###############################################################
#  Generated by:      Cadence Innovus 20.13-s083_1
#  OS:                Linux x86_64(Host ID rice-503-20-north)
#  Generated on:      Sat May 28 16:40:42 2022
#  Design:            bgr_top
#  Command:           write_lef_abstract -specifyTopLayer 6 -PGPinLayers {5 6} -noCutObs -stripePin results/bgr_top.lef
###############################################################

VERSION 5.8 ;

BUSBITCHARS "[]" ;
DIVIDERCHAR "/" ;

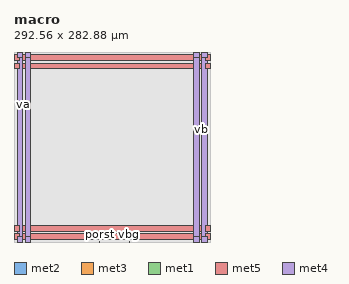
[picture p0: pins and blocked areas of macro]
MACRO macro
  CLASS BLOCK ;
  SIZE 292.560000 BY 282.880000 ;
  FOREIGN macro 0.000000 0.000000 ;
  ORIGIN 0 0 ;
  SYMMETRY X Y R90 ;
  PIN porst
    DIRECTION INOUT ;
    USE SIGNAL ;
    ANTENNAPARTIALMETALAREA 17.5123 LAYER met2  ;
    ANTENNAPARTIALMETALSIDEAREA 87.3355 LAYER met2  ;
    ANTENNAMODEL OXIDE1 ;
    ANTENNAGATEAREA 72 LAYER met2  ;
    ANTENNAMAXAREACAR 0.330333 LAYER met2  ;
    ANTENNAMAXSIDEAREACAR 1.27908 LAYER met2  ;
    ANTENNAMAXCUTCAR 0.000713889 LAYER via2  ;
    PORT
      LAYER met2 ;
        RECT 127.580000 0.000000 127.720000 0.485000 ;
    END
  END porst
  PIN va
    DIRECTION INOUT ;
    USE SIGNAL ;
    ANTENNAPARTIALMETALAREA 10.7926 LAYER met3  ;
    ANTENNAPARTIALMETALSIDEAREA 57.552 LAYER met3  ;
    ANTENNAPARTIALCUTAREA 0.04 LAYER via3  ;
    ANTENNADIFFAREA 82.639 LAYER met4  ;
    ANTENNAPARTIALMETALAREA 158.729 LAYER met4  ;
    ANTENNAPARTIALMETALSIDEAREA 645.352 LAYER met4  ;
    ANTENNAMODEL OXIDE1 ;
    ANTENNAGATEAREA 72 LAYER met4  ;
    ANTENNAMAXAREACAR 2.50947 LAYER met4  ;
    ANTENNAMAXSIDEAREACAR 10.1344 LAYER met4  ;
    ANTENNAMAXCUTCAR 0.00293611 LAYER via4  ;
    PORT
      LAYER met3 ;
        RECT 0.000000 204.870000 0.800000 205.170000 ;
    END
  END va
  PIN vb
    DIRECTION INOUT ;
    USE SIGNAL ;
    ANTENNAPARTIALMETALAREA 7.1098 LAYER met1  ;
    ANTENNAPARTIALMETALSIDEAREA 35.441 LAYER met1  ;
    ANTENNAPARTIALCUTAREA 0.0225 LAYER via  ;
    ANTENNADIFFAREA 57.9855 LAYER met2  ;
    ANTENNAPARTIALMETALAREA 18.9112 LAYER met2  ;
    ANTENNAPARTIALMETALSIDEAREA 93.996 LAYER met2  ;
    ANTENNAMODEL OXIDE1 ;
    ANTENNAGATEAREA 72 LAYER met2  ;
    ANTENNAMAXAREACAR 0.416727 LAYER met2  ;
    ANTENNAMAXSIDEAREACAR 1.70516 LAYER met2  ;
    ANTENNAMAXCUTCAR 0.000713889 LAYER via2  ;
    PORT
      LAYER met1 ;
        RECT 291.965000 167.040000 292.560000 167.180000 ;
    END
  END vb
  PIN vbg
    DIRECTION INOUT ;
    USE SIGNAL ;
    ANTENNADIFFAREA 57.9855 LAYER met2  ;
    ANTENNAPARTIALMETALAREA 16.6079 LAYER met2  ;
    ANTENNAPARTIALMETALSIDEAREA 82.8135 LAYER met2  ;
    PORT
      LAYER met2 ;
        RECT 171.740000 0.000000 171.880000 0.485000 ;
    END
  END vbg
  PIN VDD
    DIRECTION INOUT ;
    USE POWER ;
    PORT
      LAYER met5 ;
        RECT 284.400000 258.240000 292.560000 266.400000 ;
    END
    PORT
      LAYER met5 ;
        RECT 0.000000 258.240000 8.160000 266.400000 ;
    END
    PORT
      LAYER met5 ;
        RECT 284.400000 16.320000 292.560000 24.480000 ;
    END
    PORT
      LAYER met5 ;
        RECT 0.000000 16.320000 8.160000 24.480000 ;
    END
    PORT
      LAYER met4 ;
        RECT 267.280000 274.720000 275.440000 282.880000 ;
    END
    PORT
      LAYER met4 ;
        RECT 267.280000 0.000000 275.440000 8.160000 ;
    END
    PORT
      LAYER met4 ;
        RECT 16.740000 274.720000 24.900000 282.880000 ;
    END
    PORT
      LAYER met4 ;
        RECT 16.740000 0.000000 24.900000 8.160000 ;
    END

# P/G power stripe data as pin
    PORT
      LAYER met4 ;
        RECT 267.280000 0.000000 275.440000 282.880000 ;
        RECT 16.740000 0.000000 24.900000 282.880000 ;
      LAYER met5 ;
        RECT 0.000000 16.320000 292.560000 24.480000 ;
        RECT 0.000000 258.240000 292.560000 266.400000 ;
    END
# end of P/G power stripe data as pin

  END VDD
  PIN VSS
    DIRECTION INOUT ;
    USE GROUND ;
    PORT
      LAYER met5 ;
        RECT 284.400000 270.480000 292.560000 278.640000 ;
    END
    PORT
      LAYER met5 ;
        RECT 0.000000 270.480000 8.160000 278.640000 ;
    END
    PORT
      LAYER met5 ;
        RECT 284.400000 4.080000 292.560000 12.240000 ;
    END
    PORT
      LAYER met5 ;
        RECT 0.000000 4.080000 8.160000 12.240000 ;
    END
    PORT
      LAYER met4 ;
        RECT 279.520000 274.720000 287.680000 282.880000 ;
    END
    PORT
      LAYER met4 ;
        RECT 279.520000 0.000000 287.680000 8.160000 ;
    END
    PORT
      LAYER met4 ;
        RECT 4.500000 274.720000 12.660000 282.880000 ;
    END
    PORT
      LAYER met4 ;
        RECT 4.500000 0.000000 12.660000 8.160000 ;
    END

# P/G power stripe data as pin
    PORT
      LAYER met4 ;
        RECT 279.520000 0.000000 287.680000 282.880000 ;
        RECT 4.500000 0.000000 12.660000 282.880000 ;
      LAYER met5 ;
        RECT 0.000000 4.080000 292.560000 12.240000 ;
        RECT 0.000000 270.480000 292.560000 278.640000 ;
    END
# end of P/G power stripe data as pin

  END VSS
  OBS
    LAYER li1 ;
      RECT 0.000000 0.000000 292.560000 282.880000 ;
    LAYER met1 ;
      RECT 0.000000 0.000000 292.560000 282.880000 ;
    LAYER met2 ;
      RECT 0.000000 0.000000 292.560000 282.880000 ;
    LAYER met3 ;
      RECT 0.000000 0.000000 292.560000 282.880000 ;
    LAYER met4 ;
      RECT 0.000000 0.000000 292.560000 282.880000 ;
    LAYER met5 ;
      RECT 0.000000 0.000000 292.560000 282.880000 ;
  END
END macro

END LIBRARY
